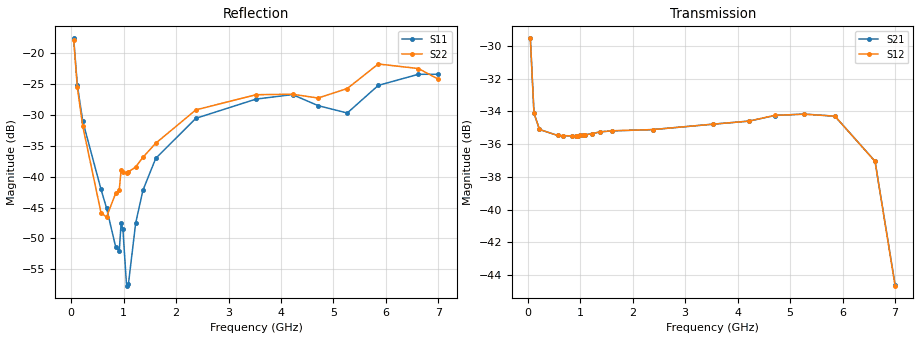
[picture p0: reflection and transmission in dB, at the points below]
! Integrated Device Technology
! Corporate Headquarters
! 6024 Silver Creek Valley Road
! San Jose, CA 95138  USA
! Phone:  1-408-284-8200
! Toll Free:  1-800-223-1366
! Webpage:  http://www.idt.com/
! Timing and RF Division
! 515 Groton Road, Suite 102
! Westford, MA 01886-6024
! Device:  F2258
! Description: Voltage Variable RF Attenuator
! Frequency:  50.0 -  6000.00 MHz
! Package:  3x3 mm Thin QFN Plastic Package: 16 pin
! Ports:  2 RF, 2 DC
!  Pin  1  = NC
!  Pin  2  = NC
!  Pin  3  = RF2  = Port 2
!  Pin  4  = GND
!  Pin  5  = Vdd
!  Pin  6  = NC
!  Pin  7  = VCTRL
!  Pin  8  = NC
!  Pin  9  = GND
!  Pin 10  = RF1  = Port 1
!  Pin 11  = NC
!  Pin 12  = NC
!  Pin 13  = NC
!  Pin 14  = NC
!  Pin 15  = NC
!  Pin 16  = NC
! Vcntrl:  2.390 Volts
! Vdd:  +3.300 Volts
! Current:  1.149 mA
! Data:  The device was measured on a the F2258 evaluation board which has
!  individual transmission lines to the RF pins.  Data was collected
!  using a calibrated network analyzer.  The evaluation board was
!  de-embedded using a TRL calibration technique.
!  The reference plane is the edge of the package pin.
! Misc:  SN 10
!  Action Tracker AT0285
! Date Measured:  2014-12-10
! Date:  2016-01-13  MJV
! Note:
!  Integrated Device Technology supplies this data as a sample of measured
!  data at the package pin for this product.  Your particular data for this
!  product may vary.
!  Data was taken at 25 degrees C.
!  Integrated Device Technology reserves the right to change this data at anytime.
!Freq_(GHz)  S11M_(dB)  S11P_(deg)  S21M_(dB)  S21P_(deg)  S12M_(dB)  S12P_(deg)  S22M_(dB)  S22P_(deg)
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# GHz S dB R 50
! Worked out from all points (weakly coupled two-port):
!   201 points, 50 MHz to 7 GHz, reference 50 ohm
!   highest |S21| = -29.54 dB at 50 MHz (marker M1); lowest = -44.6 dB at 7 GHz (marker M2)
!   lowest |S11| = -57.7 dB at 1.058 GHz (marker M3), VSWR 1.00, Z = 49.9 + j0.0578 ohm
!   |S11| at or under -10 dB: start of sweep to end of sweep
!   |S22| runs from -46.5 to -17.8 dB; largest |S21 - S12| = 7.7e-05
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0.05  -17.56 -111.0  -29.54 -68.7  -29.54 -68.7  -17.77 -111.7
0.1195  -25.12 -106.9  -34.11 -37.0  -34.11 -37.1  -25.53 -108.4
0.22375  -31.04 -110.7  -35.10 -21.4  -35.10 -21.4  -31.85 -114.3
0.57125  -42.06 -125.3  -35.47 -10.4  -35.47 -10.3  -45.86 -170.4
0.6755  -45.07 -132.4  -35.49 -9.4  -35.48 -9.4  -46.53 153.2
0.84925  -51.36 -174.2  -35.49 -8.5  -35.49 -8.5  -42.72 127.6
0.91875  -52.05 151.3  -35.48 -8.3  -35.48 -8.3  -42.09 123.8
0.9535  -47.56 -163.7  -35.49 -8.2  -35.49 -8.2  -38.98 127.4
0.98825  -48.56 -174.4  -35.47 -8.1  -35.47 -8.1  -39.28 125.2
1.05775  -57.68 153.7  -35.45 -7.9  -35.45 -7.9  -39.38 111.9
1.0925  -57.45 121.6  -35.43 -7.8  -35.43 -7.8  -39.23 107.8
1.2315  -47.51 46.8  -35.36 -7.9  -35.36 -7.8  -38.42 86.4
1.3705  -42.18 37.1  -35.25 -8.3  -35.25 -8.3  -36.85 72.4
1.61375  -37.02 33.0  -35.19 -9.5  -35.18 -9.5  -34.57 57.5
2.37825  -30.53 48.2  -35.11 -13.1  -35.11 -13.1  -29.16 45.8
3.525  -27.41 91.6  -34.78 -19.5  -34.78 -19.5  -26.70 69.0
4.22  -26.68 105.3  -34.59 -24.1  -34.59 -24.1  -26.62 76.3
4.7065  -28.47 95.7  -34.25 -28.6  -34.24 -28.5  -27.24 60.1
5.2625  -29.67 54.3  -34.16 -34.7  -34.17 -34.7  -25.70 22.8
5.85325  -25.19 29.8  -34.29 -45.3  -34.29 -45.3  -21.72 -1.5
6.61775  -23.39 49.7  -37.04 -68.6  -37.05 -68.6  -22.45 -43.5
7  -23.38 84.5  -44.58 -61.6  -44.64 -61.0  -24.19 -130.2
